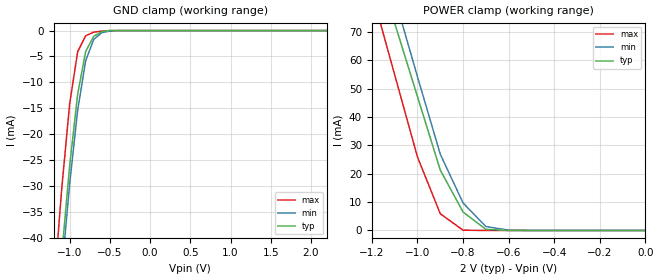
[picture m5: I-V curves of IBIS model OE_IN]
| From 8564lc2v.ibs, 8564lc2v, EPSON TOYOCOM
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[Model]   OE_IN
Model_type   Input
Polarity   Non-Inverting
Vinl =   0.6V
Vinh =   1.4V
C_comp   5pF   5pF   5pF
[Temperature Range]   25.00   85.00   -40.00
[Voltage Range]   2.0V   1.8V   2.2V
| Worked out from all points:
|   GND clamp passes 1 mA (typ) near -0.69 V on its own axis
|   POWER clamp passes 1 mA (typ) near -0.71 V on its own axis
[GND_clamp]
| voltage   I(typ)   I(min)   I(max)
-2.2V     -269mA     -264.2mA   -273.4mA
-1.2V     -63mA      -65.7mA    -50.9mA
-1.1V     -43.7mA    -47mA      -30.9mA
-1V       -26.2mA    -29.7mA    -14.2mA
-900mV    -12.3mA    -15.4mA    -4.1mA
-800mV    -4mA       -5.8mA     -1mA
-700mV    -1.1mA     -1.7mA     -300uA
-600mV    -200uA     -400uA     -100uA
-500mV    0A         -100uA     0A
2.2V      0A         0A         0A
[POWER_clamp]
| voltage   I(typ)   I(min)   I(max)
-2.2V     358mA      389mA      373.9mA
-1.2V     99mA       110mA      83.9mA
-1.1V     73.1mA     82.1mA     54.9mA
-1V       47.2mA     54.2mA     25.9mA
-900mV    21.3mA     26.9mA     5.9mA
-800mV    6.5mA      9.7mA      100uA
-700mV    400uA      1.4mA      0A
-600mV    0A         100uA      0A
0V        0A         0A         0A
